One B-rep face of a CAD part: STEP entity #527.
In plain terms, the planar face has unit normal (-1, 0, 0).
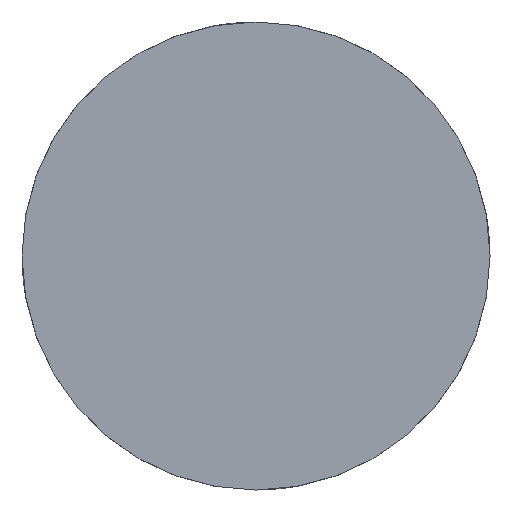
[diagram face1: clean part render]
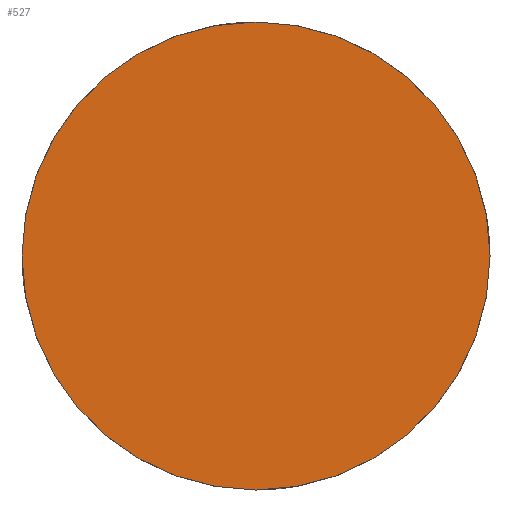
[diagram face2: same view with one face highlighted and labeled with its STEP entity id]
Its self-contained STEP definition (entity closure, numbers rounded to 3 decimals):
#459=CARTESIAN_POINT('Vertex',(-3.,0.,-3.)) ;
#462=CARTESIAN_POINT('Axis2P3D Location',(-3.,0.,0.)) ;
#466=CARTESIAN_POINT('Vertex',(-3.,3.,0.)) ;
#469=CARTESIAN_POINT('Axis2P3D Location',(-3.,0.,0.)) ;
#473=CARTESIAN_POINT('Vertex',(-3.,0.,3.)) ;
#495=CARTESIAN_POINT('Axis2P3D Location',(-3.,0.,0.)) ;
#499=CARTESIAN_POINT('Vertex',(-3.,-3.,0.)) ;
#502=CARTESIAN_POINT('Axis2P3D Location',(-3.,0.,0.)) ;
#516=CARTESIAN_POINT('Axis2P3D Location',(-3.,0.,0.)) ;
#463=DIRECTION('Axis2P3D Direction',(-1.,-0.,-0.)) ;
#470=DIRECTION('Axis2P3D Direction',(-1.,-0.,-0.)) ;
#496=DIRECTION('Axis2P3D Direction',(-1.,-0.,-0.)) ;
#503=DIRECTION('Axis2P3D Direction',(-1.,-0.,-0.)) ;
#517=DIRECTION('Axis2P3D Direction',(1.,0.,-0.)) ;
#518=DIRECTION('Axis2P3D XDirection',(-0.,0.,-1.)) ;
#464=AXIS2_PLACEMENT_3D('Circle Axis2P3D',#462,#463,$) ;
#471=AXIS2_PLACEMENT_3D('Circle Axis2P3D',#469,#470,$) ;
#497=AXIS2_PLACEMENT_3D('Circle Axis2P3D',#495,#496,$) ;
#504=AXIS2_PLACEMENT_3D('Circle Axis2P3D',#502,#503,$) ;
#519=AXIS2_PLACEMENT_3D('Plane Axis2P3D',#516,#517,#518) ;
#522=ORIENTED_EDGE('',*,*,#468,.F.) ;
#523=ORIENTED_EDGE('',*,*,#506,.F.) ;
#524=ORIENTED_EDGE('',*,*,#501,.F.) ;
#525=ORIENTED_EDGE('',*,*,#475,.F.) ;
#527=ADVANCED_FACE('359-1,5X3X125',(#526),#520,.F.) ;
#465=CIRCLE('generated circle',#464,3.) ;
#472=CIRCLE('generated circle',#471,3.) ;
#498=CIRCLE('generated circle',#497,3.) ;
#505=CIRCLE('generated circle',#504,3.) ;
#468=EDGE_CURVE('',#460,#467,#465,.F.) ;
#475=EDGE_CURVE('',#467,#474,#472,.F.) ;
#501=EDGE_CURVE('',#474,#500,#498,.F.) ;
#506=EDGE_CURVE('',#500,#460,#505,.F.) ;
#521=EDGE_LOOP('',(#522,#523,#524,#525)) ;
#526=FACE_OUTER_BOUND('',#521,.T.) ;
#520=PLANE('Plane',#519) ;
#460=VERTEX_POINT('',#459) ;
#467=VERTEX_POINT('',#466) ;
#474=VERTEX_POINT('',#473) ;
#500=VERTEX_POINT('',#499) ;
